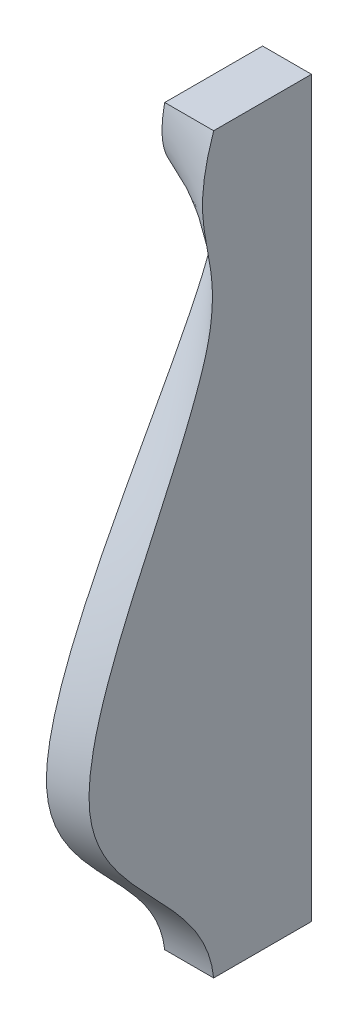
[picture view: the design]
ISO-10303-21;
HEADER;
FILE_DESCRIPTION(('STEP AP214'),'2;1');
FILE_NAME('part.step','',(''),(''),'','','');
FILE_SCHEMA(('AUTOMOTIVE_DESIGN { 1 0 10303 214 1 1 1 1 }'));
ENDSEC;
DATA;
#1=APPLICATION_CONTEXT('core data for automotive mechanical design processes');
#2=APPLICATION_PROTOCOL_DEFINITION('international standard','automotive_design',2000,#1);
#3=PRODUCT_CONTEXT('',#1,'mechanical');
#4=PRODUCT('Part','Part','',(#3));
#5=PRODUCT_RELATED_PRODUCT_CATEGORY('part','',(#4));
#6=PRODUCT_DEFINITION_FORMATION('','',#4);
#7=PRODUCT_DEFINITION_CONTEXT('part definition',#1,'design');
#8=PRODUCT_DEFINITION('design','',#6,#7);
#9=PRODUCT_DEFINITION_SHAPE('','',#8);
#10=(LENGTH_UNIT() NAMED_UNIT(*) SI_UNIT(.MILLI.,.METRE.));
#11=(NAMED_UNIT(*) PLANE_ANGLE_UNIT() SI_UNIT($,.RADIAN.));
#12=(NAMED_UNIT(*) SI_UNIT($,.STERADIAN.) SOLID_ANGLE_UNIT());
#13=UNCERTAINTY_MEASURE_WITH_UNIT(LENGTH_MEASURE(1.E-05),#10,'distance_accuracy_value','');
#14=(GEOMETRIC_REPRESENTATION_CONTEXT(3) GLOBAL_UNCERTAINTY_ASSIGNED_CONTEXT((#13)) GLOBAL_UNIT_ASSIGNED_CONTEXT((#10,
#11,#12)) REPRESENTATION_CONTEXT('',''));
#15=CARTESIAN_POINT('',(0.,0.,0.));
#16=DIRECTION('',(0.,0.,1.));
#17=DIRECTION('',(1.,0.,0.));
#18=AXIS2_PLACEMENT_3D('',#15,#16,#17);
#19=CARTESIAN_POINT('',(-50.0000000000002,375.,253.120113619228));
#20=DIRECTION('',(1.,0.,0.));
#21=DIRECTION('',(0.,0.,-1.));
#22=AXIS2_PLACEMENT_3D('',#19,#20,#21);
#23=PLANE('',#22);
#24=CARTESIAN_POINT('',(-50.0000000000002,375.,100.));
#25=CARTESIAN_POINT('',(-50.0000000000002,373.411982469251,100.545198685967));
#26=CARTESIAN_POINT('',(-50.0000000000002,371.819273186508,101.076878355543));
#27=CARTESIAN_POINT('',(-50.0000000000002,368.619545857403,102.112287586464));
#28=CARTESIAN_POINT('',(-50.0000000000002,367.012499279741,102.615928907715));
#29=CARTESIAN_POINT('',(-50.0000000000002,363.785265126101,103.592088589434));
#30=CARTESIAN_POINT('',(-50.0000000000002,362.165057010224,104.064539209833));
#31=CARTESIAN_POINT('',(-50.0000000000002,358.91265503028,104.974977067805));
#32=CARTESIAN_POINT('',(-50.0000000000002,357.280448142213,105.412917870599));
#33=CARTESIAN_POINT('',(-50.0000000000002,354.005173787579,106.250915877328));
#34=CARTESIAN_POINT('',(-50.0000000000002,352.362099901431,106.650948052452));
#35=CARTESIAN_POINT('',(-50.0000000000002,349.066198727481,107.409634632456));
#36=CARTESIAN_POINT('',(-50.0000000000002,347.413370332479,107.768284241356));
#37=CARTESIAN_POINT('',(-50.0000000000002,344.121758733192,108.436081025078));
#38=CARTESIAN_POINT('',(-50.0000000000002,342.483102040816,108.745849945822));
#39=CARTESIAN_POINT('',(-50.0000000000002,339.198566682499,109.318351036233));
#40=CARTESIAN_POINT('',(-50.0000000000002,337.552692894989,109.58111108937));
#41=CARTESIAN_POINT('',(-50.0000000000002,334.254898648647,110.056390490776));
#42=CARTESIAN_POINT('',(-50.0000000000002,332.602983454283,110.268946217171));
#43=CARTESIAN_POINT('',(-50.0000000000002,329.294313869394,110.640893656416));
#44=CARTESIAN_POINT('',(-50.0000000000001,327.637563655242,110.800322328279));
#45=CARTESIAN_POINT('',(-50.0000000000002,324.320503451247,111.063559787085));
#46=CARTESIAN_POINT('',(-50.0000000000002,322.660195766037,111.167397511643));
#47=CARTESIAN_POINT('',(-50.0000000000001,319.337335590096,111.317682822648));
#48=CARTESIAN_POINT('',(-50.0000000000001,317.674783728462,111.364144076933));
#49=CARTESIAN_POINT('',(-50.0000000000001,315.014921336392,111.391976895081));
#50=CARTESIAN_POINT('',(-50.0000000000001,314.017769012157,111.39196086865));
#51=CARTESIAN_POINT('',(-50.0000000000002,312.023543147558,111.371108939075));
#52=CARTESIAN_POINT('',(-50.0000000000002,311.026469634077,111.350270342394));
#53=CARTESIAN_POINT('',(-50.0000000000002,309.032886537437,111.288023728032));
#54=CARTESIAN_POINT('',(-50.0000000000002,308.036377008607,111.246613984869));
#55=CARTESIAN_POINT('',(-50.0000000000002,306.044380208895,111.143712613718));
#56=CARTESIAN_POINT('',(-50.0000000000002,305.04889295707,111.082220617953));
#57=CARTESIAN_POINT('',(-50.0000000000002,303.059393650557,110.939889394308));
#58=CARTESIAN_POINT('',(-50.0000000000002,302.065381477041,110.859051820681));
#59=CARTESIAN_POINT('',(-50.0000000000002,300.078665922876,110.678972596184));
#60=CARTESIAN_POINT('',(-50.0000000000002,299.085963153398,110.579724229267));
#61=CARTESIAN_POINT('',(-50.0000000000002,297.102491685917,110.364081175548));
#62=CARTESIAN_POINT('',(-50.0000000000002,296.111722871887,110.247687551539));
#63=CARTESIAN_POINT('',(-50.0000000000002,294.132144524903,109.999223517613));
#64=CARTESIAN_POINT('',(-50.0000000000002,293.143335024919,109.867152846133));
#65=CARTESIAN_POINT('',(-50.0000000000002,291.16766882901,109.589037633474));
#66=CARTESIAN_POINT('',(-50.0000000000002,290.180812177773,109.442992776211));
#67=CARTESIAN_POINT('',(-50.0000000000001,288.209016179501,109.138849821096));
#68=CARTESIAN_POINT('',(-50.0000000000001,287.224076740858,108.980752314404));
#69=CARTESIAN_POINT('',(-50.0000000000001,285.017115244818,108.615010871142));
#70=CARTESIAN_POINT('',(-50.0000000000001,283.795544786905,108.404651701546));
#71=CARTESIAN_POINT('',(-50.0000000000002,281.354453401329,107.972812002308));
#72=CARTESIAN_POINT('',(-50.0000000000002,280.134932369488,107.751332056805));
#73=CARTESIAN_POINT('',(-50.0000000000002,277.697092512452,107.301721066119));
#74=CARTESIAN_POINT('',(-50.0000000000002,276.478773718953,107.073589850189));
#75=CARTESIAN_POINT('',(-50.0000000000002,274.042478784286,106.615227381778));
#76=CARTESIAN_POINT('',(-50.0000000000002,272.824502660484,106.384996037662));
#77=CARTESIAN_POINT('',(-50.0000000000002,270.388187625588,105.926958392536));
#78=CARTESIAN_POINT('',(-50.0000000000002,269.169848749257,105.699151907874));
#79=CARTESIAN_POINT('',(-50.0000000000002,266.731957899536,105.250267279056));
#80=CARTESIAN_POINT('',(-50.0000000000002,265.512405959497,105.029188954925));
#81=CARTESIAN_POINT('',(-50.0000000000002,263.071441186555,104.597787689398));
#82=CARTESIAN_POINT('',(-50.0000000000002,261.850028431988,104.387464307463));
#83=CARTESIAN_POINT('',(-50.0000000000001,259.404766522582,103.981202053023));
#84=CARTESIAN_POINT('',(-50.0000000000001,258.180917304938,103.785263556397));
#85=CARTESIAN_POINT('',(-50.0000000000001,255.725906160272,103.410271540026));
#86=CARTESIAN_POINT('',(-50.0000000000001,254.494734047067,103.231284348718));
#87=CARTESIAN_POINT('',(-50.0000000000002,252.029566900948,102.893774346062));
#88=CARTESIAN_POINT('',(-50.0000000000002,250.795571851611,102.735251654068));
#89=CARTESIAN_POINT('',(-50.0000000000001,248.324845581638,102.440907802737));
#90=CARTESIAN_POINT('',(-50.0000000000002,247.088114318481,102.30508699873));
#91=CARTESIAN_POINT('',(-50.0000000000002,244.612204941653,102.057897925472));
#92=CARTESIAN_POINT('',(-50.0000000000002,243.373026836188,101.946529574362));
#93=CARTESIAN_POINT('',(-50.0000000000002,240.892541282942,101.74953172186));
#94=CARTESIAN_POINT('',(-50.0000000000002,239.651233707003,101.663903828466));
#95=CARTESIAN_POINT('',(-50.0000000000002,237.167053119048,101.519287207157));
#96=CARTESIAN_POINT('',(-50.0000000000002,235.924180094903,101.460298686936));
#97=CARTESIAN_POINT('',(-50.0000000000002,233.437450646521,101.369514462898));
#98=CARTESIAN_POINT('',(-50.0000000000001,232.193594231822,101.337718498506));
#99=CARTESIAN_POINT('',(-50.0000000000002,229.705512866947,101.301597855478));
#100=CARTESIAN_POINT('',(-50.0000000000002,228.461287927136,101.297272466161));
#101=CARTESIAN_POINT('',(-50.0000000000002,226.014355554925,101.315845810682));
#102=CARTESIAN_POINT('',(-50.0000000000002,224.811641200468,101.337845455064));
#103=CARTESIAN_POINT('',(-50.0000000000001,222.406947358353,101.407509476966));
#104=CARTESIAN_POINT('',(-50.0000000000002,221.204967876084,101.455174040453));
#105=CARTESIAN_POINT('',(-50.0000000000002,218.802219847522,101.57600354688));
#106=CARTESIAN_POINT('',(-50.0000000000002,217.601451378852,101.649170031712));
#107=CARTESIAN_POINT('',(-50.0000000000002,215.20159708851,101.820780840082));
#108=CARTESIAN_POINT('',(-50.0000000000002,214.002511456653,101.91922781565));
#109=CARTESIAN_POINT('',(-50.0000000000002,211.607293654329,102.1410660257));
#110=CARTESIAN_POINT('',(-50.0000000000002,210.411160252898,102.2644439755));
#111=CARTESIAN_POINT('',(-50.0000000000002,208.021735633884,102.53587570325));
#112=CARTESIAN_POINT('',(-50.0000000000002,206.828444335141,102.683928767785));
#113=CARTESIAN_POINT('',(-50.0000000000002,204.445356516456,103.004369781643));
#114=CARTESIAN_POINT('',(-50.0000000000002,203.255559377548,103.176753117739));
#115=CARTESIAN_POINT('',(-50.0000000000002,201.473899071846,103.453307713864));
#116=CARTESIAN_POINT('',(-50.0000000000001,200.880624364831,103.548470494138));
#117=CARTESIAN_POINT('',(-50.0000000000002,199.695052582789,103.744754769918));
#118=CARTESIAN_POINT('',(-50.0000000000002,199.102755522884,103.845876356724));
#119=CARTESIAN_POINT('',(-50.0000000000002,197.130475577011,104.192750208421));
#120=CARTESIAN_POINT('',(-50.0000000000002,195.75278139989,104.451640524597));
#121=CARTESIAN_POINT('',(-50.0000000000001,193.003675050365,105.001008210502));
#122=CARTESIAN_POINT('',(-50.0000000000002,191.632263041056,105.291486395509));
#123=CARTESIAN_POINT('',(-50.0000000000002,189.580210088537,105.750428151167));
#124=CARTESIAN_POINT('',(-50.0000000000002,188.896957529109,105.90729905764));
#125=CARTESIAN_POINT('',(-50.0000000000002,187.532247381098,106.228672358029));
#126=CARTESIAN_POINT('',(-50.0000000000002,186.85078978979,106.393174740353));
#127=CARTESIAN_POINT('',(-50.0000000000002,185.489760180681,106.729773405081));
#128=CARTESIAN_POINT('',(-50.0000000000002,184.810188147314,106.90186962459));
#129=CARTESIAN_POINT('',(-50.0000000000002,183.452899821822,107.253227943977));
#130=CARTESIAN_POINT('',(-50.0000000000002,182.775183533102,107.432490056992));
#131=CARTESIAN_POINT('',(-50.0000000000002,181.420723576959,107.797758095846));
#132=CARTESIAN_POINT('',(-50.0000000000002,180.74398196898,107.983771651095));
#133=CARTESIAN_POINT('',(-50.0000000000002,179.392190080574,108.361835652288));
#134=CARTESIAN_POINT('',(-50.0000000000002,178.717139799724,108.553886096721));
#135=CARTESIAN_POINT('',(-50.0000000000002,176.694391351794,109.138372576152));
#136=CARTESIAN_POINT('',(-50.0000000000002,175.349096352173,109.539143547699));
#137=CARTESIAN_POINT('',(-50.0000000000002,172.662564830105,110.360205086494));
#138=CARTESIAN_POINT('',(-50.0000000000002,171.32133597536,110.780520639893));
#139=CARTESIAN_POINT('',(-50.0000000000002,168.644137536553,111.637527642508));
#140=CARTESIAN_POINT('',(-50.0000000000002,167.308167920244,112.07421899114));
#141=CARTESIAN_POINT('',(-50.0000000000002,164.639977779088,112.962081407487));
#142=CARTESIAN_POINT('',(-50.0000000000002,163.307760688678,113.41326277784));
#143=CARTESIAN_POINT('',(-50.0000000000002,160.647555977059,114.327931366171));
#144=CARTESIAN_POINT('',(-50.0000000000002,159.31956837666,114.791418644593));
#145=CARTESIAN_POINT('',(-50.0000000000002,156.66765038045,115.728992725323));
#146=CARTESIAN_POINT('',(-50.0000000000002,155.343719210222,116.203077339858));
#147=CARTESIAN_POINT('',(-50.0000000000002,152.699244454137,117.16059124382));
#148=CARTESIAN_POINT('',(-50.0000000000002,151.378700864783,117.644020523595));
#149=CARTESIAN_POINT('',(-50.0000000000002,148.729259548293,118.623985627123));
#150=CARTESIAN_POINT('',(-50.0000000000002,147.40039064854,119.12059937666));
#151=CARTESIAN_POINT('',(-50.0000000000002,144.745842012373,120.122270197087));
#152=CARTESIAN_POINT('',(-50.0000000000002,143.420162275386,120.627327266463));
#153=CARTESIAN_POINT('',(-50.0000000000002,139.450536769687,122.153367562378));
#154=CARTESIAN_POINT('',(-50.0000000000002,136.811166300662,123.186272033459));
#155=CARTESIAN_POINT('',(-50.0000000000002,131.545797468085,125.279632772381));
#156=CARTESIAN_POINT('',(-50.0000000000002,128.919790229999,126.340066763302));
#157=CARTESIAN_POINT('',(-50.0000000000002,123.67954195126,128.485549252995));
#158=CARTESIAN_POINT('',(-50.0000000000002,121.065295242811,129.570583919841));
#159=CARTESIAN_POINT('',(-50.0000000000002,115.847026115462,131.76244788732));
#160=CARTESIAN_POINT('',(-50.0000000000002,113.243000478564,132.869269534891));
#161=CARTESIAN_POINT('',(-50.0000000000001,108.043661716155,135.101966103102));
#162=CARTESIAN_POINT('',(-50.0000000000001,105.448347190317,136.227837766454));
#163=CARTESIAN_POINT('',(-50.0000000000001,97.4585446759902,139.723914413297));
#164=CARTESIAN_POINT('',(-50.0000000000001,92.0760164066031,142.121443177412));
#165=CARTESIAN_POINT('',(-50.0000000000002,81.3307462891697,146.963298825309));
#166=CARTESIAN_POINT('',(-50.0000000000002,75.96800903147,149.40763584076));
#167=CARTESIAN_POINT('',(-50.0000000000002,65.2512156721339,154.320720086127));
#168=CARTESIAN_POINT('',(-50.0000000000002,59.8971637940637,156.789476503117));
#169=CARTESIAN_POINT('',(-50.0000000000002,49.1874266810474,161.730610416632));
#170=CARTESIAN_POINT('',(-50.0000000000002,43.8317420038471,164.202989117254));
#171=CARTESIAN_POINT('',(-50.0000000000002,33.1089723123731,169.131773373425));
#172=CARTESIAN_POINT('',(-50.0000000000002,27.7418822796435,171.588168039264));
#173=CARTESIAN_POINT('',(-50.0000000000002,16.9867450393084,176.465915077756));
#174=CARTESIAN_POINT('',(-50.0000000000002,11.598684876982,178.887239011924));
#175=CARTESIAN_POINT('',(-50.0000000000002,3.51580203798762,182.468460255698));
#176=CARTESIAN_POINT('',(-50.0000000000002,0.830489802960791,183.649815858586));
#177=CARTESIAN_POINT('',(-50.0000000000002,-4.54738764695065,185.995890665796));
#178=CARTESIAN_POINT('',(-50.0000000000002,-7.23995283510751,187.160609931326));
#179=CARTESIAN_POINT('',(-50.0000000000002,-12.6336507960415,189.470838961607));
#180=CARTESIAN_POINT('',(-50.0000000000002,-15.3347844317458,190.616346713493));
#181=CARTESIAN_POINT('',(-50.0000000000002,-20.7463716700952,192.885153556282));
#182=CARTESIAN_POINT('',(-50.0000000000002,-23.4568252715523,194.008452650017));
#183=CARTESIAN_POINT('',(-50.0000000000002,-28.8866154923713,196.229144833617));
#184=CARTESIAN_POINT('',(-50.0000000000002,-31.6059464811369,197.326551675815));
#185=CARTESIAN_POINT('',(-50.0000000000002,-37.0560076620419,199.49272890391));
#186=CARTESIAN_POINT('',(-50.0000000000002,-39.786737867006,200.56149925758));
#187=CARTESIAN_POINT('',(-50.0000000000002,-45.2580758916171,202.66571006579));
#188=CARTESIAN_POINT('',(-50.0000000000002,-47.9986719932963,203.70118094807));
#189=CARTESIAN_POINT('',(-50.0000000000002,-53.4933482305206,205.73573753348));
#190=CARTESIAN_POINT('',(-50.0000000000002,-56.2474283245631,206.73482334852));
#191=CARTESIAN_POINT('',(-50.0000000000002,-61.7675105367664,208.691072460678));
#192=CARTESIAN_POINT('',(-50.0000000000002,-64.5334988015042,209.648274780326));
#193=CARTESIAN_POINT('',(-50.0000000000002,-70.0810788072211,211.516571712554));
#194=CARTESIAN_POINT('',(-50.0000000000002,-72.8626707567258,212.42766570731));
#195=CARTESIAN_POINT('',(-50.0000000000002,-78.4416543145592,214.197529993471));
#196=CARTESIAN_POINT('',(-50.0000000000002,-81.2390414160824,215.056314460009));
#197=CARTESIAN_POINT('',(-50.0000000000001,-86.8511709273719,216.714934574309));
#198=CARTESIAN_POINT('',(-50.0000000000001,-89.6659125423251,217.51477290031));
#199=CARTESIAN_POINT('',(-50.0000000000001,-94.6743474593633,218.874027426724));
#200=CARTESIAN_POINT('',(-50.0000000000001,-96.8643935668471,219.446882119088));
#201=CARTESIAN_POINT('',(-50.0000000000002,-101.25595796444,220.548333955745));
#202=CARTESIAN_POINT('',(-50.0000000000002,-103.457477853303,221.076924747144));
#203=CARTESIAN_POINT('',(-50.0000000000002,-107.871991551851,222.084960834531));
#204=CARTESIAN_POINT('',(-50.0000000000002,-110.084986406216,222.56440157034));
#205=CARTESIAN_POINT('',(-50.0000000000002,-114.522606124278,223.468640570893));
#206=CARTESIAN_POINT('',(-50.0000000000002,-116.74723315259,223.893428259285));
#207=CARTESIAN_POINT('',(-50.0000000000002,-121.204627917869,224.681442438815));
#208=CARTESIAN_POINT('',(-50.0000000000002,-123.437382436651,225.044743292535));
#209=CARTESIAN_POINT('',(-50.0000000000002,-127.913023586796,225.703184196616));
#210=CARTESIAN_POINT('',(-50.0000000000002,-130.155910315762,225.998323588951));
#211=CARTESIAN_POINT('',(-50.0000000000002,-134.650160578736,226.512094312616));
#212=CARTESIAN_POINT('',(-50.0000000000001,-136.901522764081,226.730737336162));
#213=CARTESIAN_POINT('',(-50.0000000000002,-141.41131933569,227.082095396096));
#214=CARTESIAN_POINT('',(-50.0000000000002,-143.669754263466,227.21480368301));
#215=CARTESIAN_POINT('',(-50.0000000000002,-147.313616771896,227.350686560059));
#216=CARTESIAN_POINT('',(-50.0000000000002,-148.697949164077,227.384136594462));
#217=CARTESIAN_POINT('',(-50.0000000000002,-151.467085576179,227.411976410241));
#218=CARTESIAN_POINT('',(-50.0000000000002,-152.851889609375,227.406364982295));
#219=CARTESIAN_POINT('',(-50.0000000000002,-155.620457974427,227.353140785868));
#220=CARTESIAN_POINT('',(-50.0000000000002,-157.004222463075,227.305536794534));
#221=CARTESIAN_POINT('',(-50.0000000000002,-159.077945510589,227.200299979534));
#222=CARTESIAN_POINT('',(-50.0000000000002,-159.768792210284,227.159588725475));
#223=CARTESIAN_POINT('',(-50.0000000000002,-161.149705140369,227.066480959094));
#224=CARTESIAN_POINT('',(-50.0000000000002,-161.839771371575,227.014084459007));
#225=CARTESIAN_POINT('',(-50.0000000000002,-163.21884301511,226.897196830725));
#226=CARTESIAN_POINT('',(-50.0000000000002,-163.907848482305,226.832706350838));
#227=CARTESIAN_POINT('',(-50.0000000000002,-165.284572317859,226.69119482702));
#228=CARTESIAN_POINT('',(-50.0000000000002,-165.972290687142,226.614173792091));
#229=CARTESIAN_POINT('',(-50.0000000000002,-167.344498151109,226.447780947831));
#230=CARTESIAN_POINT('',(-50.0000000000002,-168.028991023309,226.358440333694));
#231=CARTESIAN_POINT('',(-50.0000000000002,-169.396224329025,226.167279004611));
#232=CARTESIAN_POINT('',(-50.0000000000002,-170.078964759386,226.065458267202));
#233=CARTESIAN_POINT('',(-50.0000000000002,-172.124612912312,225.741255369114));
#234=CARTESIAN_POINT('',(-50.0000000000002,-173.484607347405,225.500173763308));
#235=CARTESIAN_POINT('',(-50.0000000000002,-176.195149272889,224.968679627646));
#236=CARTESIAN_POINT('',(-50.0000000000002,-177.545694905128,224.678257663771));
#237=CARTESIAN_POINT('',(-50.0000000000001,-180.235587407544,224.049109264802));
#238=CARTESIAN_POINT('',(-50.0000000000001,-181.57493353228,223.710379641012));
#239=CARTESIAN_POINT('',(-50.0000000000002,-184.240605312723,222.985687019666));
#240=CARTESIAN_POINT('',(-50.0000000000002,-185.566932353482,222.59972910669));
#241=CARTESIAN_POINT('',(-50.0000000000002,-188.53155439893,221.680531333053));
#242=CARTESIAN_POINT('',(-50.0000000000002,-190.165888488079,221.134472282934));
#243=CARTESIAN_POINT('',(-50.0000000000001,-193.410064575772,219.973460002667));
#244=CARTESIAN_POINT('',(-50.0000000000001,-195.019903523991,219.358498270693));
#245=CARTESIAN_POINT('',(-50.0000000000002,-198.212818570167,218.063297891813));
#246=CARTESIAN_POINT('',(-50.0000000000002,-199.795898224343,217.383068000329));
#247=CARTESIAN_POINT('',(-50.0000000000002,-202.934127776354,215.961203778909));
#248=CARTESIAN_POINT('',(-50.0000000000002,-204.489278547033,215.219571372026));
#249=CARTESIAN_POINT('',(-50.0000000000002,-207.574998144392,213.677064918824));
#250=CARTESIAN_POINT('',(-50.0000000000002,-209.105491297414,212.876039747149));
#251=CARTESIAN_POINT('',(-50.0000000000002,-212.137461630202,211.220886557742));
#252=CARTESIAN_POINT('',(-50.0000000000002,-213.638938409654,210.366757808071));
#253=CARTESIAN_POINT('',(-50.0000000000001,-216.613104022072,208.609890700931));
#254=CARTESIAN_POINT('',(-50.0000000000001,-218.085793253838,207.707153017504));
#255=CARTESIAN_POINT('',(-50.0000000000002,-221.003169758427,205.85746014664));
#256=CARTESIAN_POINT('',(-50.0000000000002,-222.447855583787,204.910502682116));
#257=CARTESIAN_POINT('',(-50.0000000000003,-226.047939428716,202.478358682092));
#258=CARTESIAN_POINT('',(-50.0000000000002,-228.185888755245,200.967308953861));
#259=CARTESIAN_POINT('',(-50.0000000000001,-232.405149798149,197.867873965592));
#260=CARTESIAN_POINT('',(-50.0000000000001,-234.486453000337,196.279477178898));
#261=CARTESIAN_POINT('',(-50.0000000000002,-238.599227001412,193.038251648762));
#262=CARTESIAN_POINT('',(-50.0000000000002,-240.630681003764,191.385401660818));
#263=CARTESIAN_POINT('',(-50.0000000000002,-244.650240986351,188.02795883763));
#264=CARTESIAN_POINT('',(-50.0000000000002,-246.638346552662,186.323365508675));
#265=CARTESIAN_POINT('',(-50.0000000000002,-250.582685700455,182.870344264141));
#266=CARTESIAN_POINT('',(-50.0000000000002,-252.538851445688,181.121839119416));
#267=CARTESIAN_POINT('',(-50.0000000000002,-256.422984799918,177.595013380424));
#268=CARTESIAN_POINT('',(-50.0000000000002,-258.350960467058,175.816701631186));
#269=CARTESIAN_POINT('',(-50.0000000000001,-262.187478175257,172.239609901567));
#270=CARTESIAN_POINT('',(-50.0000000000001,-264.096021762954,170.440831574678));
#271=CARTESIAN_POINT('',(-50.0000000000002,-267.902261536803,166.831967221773));
#272=CARTESIAN_POINT('',(-50.0000000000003,-269.799957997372,165.021881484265));
#273=CARTESIAN_POINT('',(-50.0000000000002,-273.243548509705,161.733269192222));
#274=CARTESIAN_POINT('',(-50.0000000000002,-274.789811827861,160.255128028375));
#275=CARTESIAN_POINT('',(-50.0000000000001,-277.885564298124,157.302255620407));
#276=CARTESIAN_POINT('',(-50.0000000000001,-279.435053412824,155.82752433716));
#277=CARTESIAN_POINT('',(-50.0000000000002,-282.542093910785,152.886426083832));
#278=CARTESIAN_POINT('',(-50.0000000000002,-284.099645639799,151.420059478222));
#279=CARTESIAN_POINT('',(-50.0000000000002,-287.227770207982,148.500773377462));
#280=CARTESIAN_POINT('',(-50.0000000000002,-288.798344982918,147.047855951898));
#281=CARTESIAN_POINT('',(-50.0000000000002,-291.957647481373,144.160733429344));
#282=CARTESIAN_POINT('',(-50.0000000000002,-293.546381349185,142.726535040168));
#283=CARTESIAN_POINT('',(-50.0000000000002,-296.742703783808,139.886496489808));
#284=CARTESIAN_POINT('',(-50.0000000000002,-298.35024229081,138.480600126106));
#285=CARTESIAN_POINT('',(-50.0000000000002,-301.59250613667,135.700183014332));
#286=CARTESIAN_POINT('',(-50.0000000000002,-303.227233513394,134.325664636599));
#287=CARTESIAN_POINT('',(-50.0000000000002,-306.527918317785,131.615491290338));
#288=CARTESIAN_POINT('',(-50.0000000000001,-308.193866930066,130.279825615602));
#289=CARTESIAN_POINT('',(-50.0000000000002,-311.561222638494,127.655095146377));
#290=CARTESIAN_POINT('',(-50.0000000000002,-313.262616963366,126.366014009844));
#291=CARTESIAN_POINT('',(-50.0000000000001,-316.70533439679,123.842420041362));
#292=CARTESIAN_POINT('',(-50.0000000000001,-318.446654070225,122.6079025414));
#293=CARTESIAN_POINT('',(-50.0000000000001,-321.605045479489,120.453299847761));
#294=CARTESIAN_POINT('',(-50.0000000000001,-323.014007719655,119.521330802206));
#295=CARTESIAN_POINT('',(-50.0000000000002,-325.860656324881,117.701936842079));
#296=CARTESIAN_POINT('',(-50.0000000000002,-327.298345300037,116.814516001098));
#297=CARTESIAN_POINT('',(-50.0000000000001,-330.203280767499,115.089321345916));
#298=CARTESIAN_POINT('',(-50.0000000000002,-331.670527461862,114.251547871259));
#299=CARTESIAN_POINT('',(-50.0000000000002,-334.635353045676,112.630622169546));
#300=CARTESIAN_POINT('',(-50.0000000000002,-336.132938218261,111.847481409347));
#301=CARTESIAN_POINT('',(-50.0000000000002,-339.153065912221,110.343647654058));
#302=CARTESIAN_POINT('',(-50.0000000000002,-340.6755103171,109.622758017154));
#303=CARTESIAN_POINT('',(-50.0000000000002,-343.749495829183,108.245490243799));
#304=CARTESIAN_POINT('',(-50.0000000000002,-345.301038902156,107.589116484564));
#305=CARTESIAN_POINT('',(-50.0000000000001,-348.431147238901,106.345826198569));
#306=CARTESIAN_POINT('',(-50.0000000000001,-350.009703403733,105.758886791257));
#307=CARTESIAN_POINT('',(-50.0000000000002,-353.191582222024,104.658630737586));
#308=CARTESIAN_POINT('',(-50.0000000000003,-354.79489311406,104.145280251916));
#309=CARTESIAN_POINT('',(-50.0000000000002,-357.166677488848,103.447598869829));
#310=CARTESIAN_POINT('',(-50.0000000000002,-357.926439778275,103.233288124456));
#311=CARTESIAN_POINT('',(-50.0000000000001,-359.45052112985,102.821870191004));
#312=CARTESIAN_POINT('',(-50.0000000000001,-360.214839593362,102.624760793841));
#313=CARTESIAN_POINT('',(-50.0000000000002,-361.747685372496,102.247995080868));
#314=CARTESIAN_POINT('',(-50.0000000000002,-362.516212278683,102.068337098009));
#315=CARTESIAN_POINT('',(-50.0000000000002,-364.057138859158,101.726665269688));
#316=CARTESIAN_POINT('',(-50.0000000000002,-364.829538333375,101.564650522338));
#317=CARTESIAN_POINT('',(-50.0000000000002,-366.380628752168,101.257864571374));
#318=CARTESIAN_POINT('',(-50.0000000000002,-367.159332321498,101.113157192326));
#319=CARTESIAN_POINT('',(-50.0000000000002,-368.71991517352,100.841762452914));
#320=CARTESIAN_POINT('',(-50.0000000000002,-369.501794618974,100.71507602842));
#321=CARTESIAN_POINT('',(-50.0000000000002,-371.068358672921,100.479778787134));
#322=CARTESIAN_POINT('',(-50.0000000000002,-371.853043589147,100.371170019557));
#323=CARTESIAN_POINT('',(-50.0000000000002,-373.42484081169,100.172023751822));
#324=CARTESIAN_POINT('',(-50.0000000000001,-374.211953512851,100.081489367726));
#325=CARTESIAN_POINT('',(-50.0000000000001,-375.,100.));
#326=B_SPLINE_CURVE_WITH_KNOTS('',3,(#24,#25,#26,#27,#28,#29,#30,#31,#32,#33,#34,#35,#36,#37,
#38,#39,#40,#41,#42,#43,#44,#45,#46,#47,#48,#49,#50,#51,#52,#53,#54,#55,#56,#57,#58,#59,#60,#61,
#62,#63,#64,#65,#66,#67,#68,#69,#70,#71,#72,#73,#74,#75,#76,#77,#78,#79,#80,#81,#82,#83,#84,#85,
#86,#87,#88,#89,#90,#91,#92,#93,#94,#95,#96,#97,#98,#99,#100,#101,#102,#103,#104,#105,#106,#107,
#108,#109,#110,#111,#112,#113,#114,#115,#116,#117,#118,#119,#120,#121,#122,#123,#124,#125,#126,
#127,#128,#129,#130,#131,#132,#133,#134,#135,#136,#137,#138,#139,#140,#141,#142,#143,#144,#145,
#146,#147,#148,#149,#150,#151,#152,#153,#154,#155,#156,#157,#158,#159,#160,#161,#162,#163,#164,
#165,#166,#167,#168,#169,#170,#171,#172,#173,#174,#175,#176,#177,#178,#179,#180,#181,#182,#183,
#184,#185,#186,#187,#188,#189,#190,#191,#192,#193,#194,#195,#196,#197,#198,#199,#200,#201,#202,
#203,#204,#205,#206,#207,#208,#209,#210,#211,#212,#213,#214,#215,#216,#217,#218,#219,#220,#221,
#222,#223,#224,#225,#226,#227,#228,#229,#230,#231,#232,#233,#234,#235,#236,#237,#238,#239,#240,
#241,#242,#243,#244,#245,#246,#247,#248,#249,#250,#251,#252,#253,#254,#255,#256,#257,#258,#259,
#260,#261,#262,#263,#264,#265,#266,#267,#268,#269,#270,#271,#272,#273,#274,#275,#276,#277,#278,
#279,#280,#281,#282,#283,#284,#285,#286,#287,#288,#289,#290,#291,#292,#293,#294,#295,#296,#297,
#298,#299,#300,#301,#302,#303,#304,#305,#306,#307,#308,#309,#310,#311,#312,#313,#314,#315,#316,
#317,#318,#319,#320,#321,#322,#323,#324,#325),.UNSPECIFIED.,.F.,.F.,(4,2,2,2,2,2,2,2,2,2,2,2,2,
2,2,2,2,2,2,2,2,2,2,2,2,2,2,2,2,2,2,2,2,2,2,2,2,2,2,2,2,2,2,2,2,2,2,2,2,2,2,2,2,2,2,2,2,2,2,2,2,
2,2,2,2,2,2,2,2,2,2,2,2,2,2,2,2,2,2,2,2,2,2,2,2,2,2,2,2,2,2,2,2,2,2,2,2,2,2,2,2,2,2,2,2,2,2,2,2,
2,2,2,2,2,2,2,2,2,2,2,2,2,2,2,2,2,2,2,2,2,2,2,2,2,2,2,2,2,2,2,2,2,2,2,2,2,2,2,2,2,4),(0.,
5.03701006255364,10.0890671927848,15.1517580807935,20.2211487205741,25.2938633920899,
30.3671653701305,35.3695687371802,40.3689950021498,45.3647874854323,50.3570972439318,
55.3468057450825,60.3353254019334,63.3265896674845,66.3182409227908,69.3101431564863,
72.3021001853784,75.2938014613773,78.2865962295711,81.2792055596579,84.2718648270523,
87.26459180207,90.25717208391,93.9757457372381,97.6941242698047,101.412598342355,
105.131235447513,108.849588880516,112.567842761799,116.285944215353,120.004142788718,
123.736336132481,127.468551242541,131.2008247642,134.933085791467,138.665579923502,
142.398103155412,146.130590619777,149.862981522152,153.471454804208,157.079954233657,
160.688671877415,164.297768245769,167.904946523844,171.512020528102,175.118411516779,
176.920960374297,178.723536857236,182.928555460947,187.13368262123,189.236734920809,
191.339784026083,193.442815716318,195.545851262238,197.651342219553,199.75683265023,
203.967815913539,208.184339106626,212.400836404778,216.620401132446,220.839986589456,
225.058708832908,229.277426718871,233.53329223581,237.789156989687,246.291805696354,
254.787776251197,263.279082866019,271.767458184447,280.254396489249,297.931030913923,
315.611535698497,333.298966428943,350.995409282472,368.702857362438,386.423939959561,
395.224946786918,404.025921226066,412.82781208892,421.629701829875,430.426806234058,
439.223920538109,448.012753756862,456.801559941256,465.581995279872,474.362548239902,
483.140711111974,491.918474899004,498.709256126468,505.501010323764,512.293394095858,
519.087090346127,525.872510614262,532.657996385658,539.442444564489,546.227425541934,
550.381159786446,554.535022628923,558.688017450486,560.764071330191,562.840123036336,
564.916063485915,566.99200244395,569.062778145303,571.133557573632,575.276143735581,
579.419522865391,583.563175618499,587.706382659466,592.874156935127,598.042569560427,
603.210289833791,608.377848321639,613.559039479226,618.740302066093,623.921492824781,
629.102950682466,636.954848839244,644.807920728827,652.663603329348,660.519360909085,
668.390064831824,676.258473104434,684.126250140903,691.993827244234,698.411187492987,
704.828473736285,711.246037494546,717.664572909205,724.085348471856,730.491777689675,
736.898689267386,743.303818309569,749.706678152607,756.108989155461,761.176161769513,
766.243796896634,771.31146667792,776.380196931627,781.432280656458,786.484706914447,
791.535463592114,796.583890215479,798.951958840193,801.319722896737,803.687260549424,
806.054677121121,808.430571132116,810.806588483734,813.182874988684,815.559570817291),.UNSPECIFIED.);
#327=CARTESIAN_POINT('',(-50.0000000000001,375.,100.));
#328=VERTEX_POINT('',#327);
#329=CARTESIAN_POINT('',(-50.0000000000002,-375.,100.));
#330=VERTEX_POINT('',#329);
#331=EDGE_CURVE('E88',#328,#330,#326,.T.);
#332=ORIENTED_EDGE('',*,*,#331,.T.);
#333=DIRECTION('',(0.,0.,-1.));
#334=VECTOR('',#333,1.);
#335=CARTESIAN_POINT('',(-50.0000000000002,-375.,253.120113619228));
#336=LINE('',#335,#334);
#337=CARTESIAN_POINT('',(-50.0000000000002,-375.,0.));
#338=VERTEX_POINT('',#337);
#339=EDGE_CURVE('E50',#330,#338,#336,.T.);
#340=ORIENTED_EDGE('',*,*,#339,.T.);
#341=DIRECTION('',(0.,-1.,0.));
#342=VECTOR('',#341,1.);
#343=CARTESIAN_POINT('',(-50.0000000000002,375.,0.));
#344=LINE('',#343,#342);
#345=CARTESIAN_POINT('',(-50.0000000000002,375.,0.));
#346=VERTEX_POINT('',#345);
#347=EDGE_CURVE('E87',#346,#338,#344,.T.);
#348=ORIENTED_EDGE('',*,*,#347,.F.);
#349=DIRECTION('',(0.,0.,-1.));
#350=VECTOR('',#349,1.);
#351=CARTESIAN_POINT('',(-50.0000000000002,375.,253.120113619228));
#352=LINE('',#351,#350);
#353=EDGE_CURVE('E65',#328,#346,#352,.T.);
#354=ORIENTED_EDGE('',*,*,#353,.F.);
#355=EDGE_LOOP('',(#332,#340,#348,#354));
#356=FACE_BOUND('',#355,.T.);
#357=ADVANCED_FACE('F35',(#356),#23,.T.);
#358=CARTESIAN_POINT('',(0.,0.,0.));
#359=DIRECTION('',(0.,0.,-1.));
#360=DIRECTION('',(-1.,0.,0.));
#361=AXIS2_PLACEMENT_3D('',#358,#359,#360);
#362=PLANE('',#361);
#363=DIRECTION('',(1.,0.,0.));
#364=VECTOR('',#363,1.);
#365=CARTESIAN_POINT('',(-750.,-375.,0.));
#366=LINE('',#365,#364);
#367=CARTESIAN_POINT('',(-100.,-375.,0.));
#368=VERTEX_POINT('',#367);
#369=EDGE_CURVE('E79',#368,#338,#366,.T.);
#370=ORIENTED_EDGE('',*,*,#369,.F.);
#371=DIRECTION('',(0.,1.,0.));
#372=VECTOR('',#371,1.);
#373=CARTESIAN_POINT('',(-100.,375.,0.));
#374=LINE('',#373,#372);
#375=CARTESIAN_POINT('',(-100.,375.,0.));
#376=VERTEX_POINT('',#375);
#377=EDGE_CURVE('E157',#368,#376,#374,.T.);
#378=ORIENTED_EDGE('',*,*,#377,.T.);
#379=DIRECTION('',(-1.,0.,0.));
#380=VECTOR('',#379,1.);
#381=CARTESIAN_POINT('',(-750.,375.,0.));
#382=LINE('',#381,#380);
#383=EDGE_CURVE('E93',#346,#376,#382,.T.);
#384=ORIENTED_EDGE('',*,*,#383,.F.);
#385=ORIENTED_EDGE('',*,*,#347,.T.);
#386=EDGE_LOOP('',(#370,#378,#384,#385));
#387=FACE_BOUND('',#386,.T.);
#388=ADVANCED_FACE('F91',(#387),#362,.T.);
#389=CARTESIAN_POINT('',(750.,-375.,100.));
#390=CARTESIAN_POINT('',(750.,-302.078506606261,100.));
#391=CARTESIAN_POINT('',(750.,-224.483786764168,100.));
#392=CARTESIAN_POINT('',(750.,-61.5160152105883,100.));
#393=CARTESIAN_POINT('',(750.,39.4445673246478,100.));
#394=CARTESIAN_POINT('',(750.,211.849847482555,100.));
#395=CARTESIAN_POINT('',(750.,298.882075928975,100.));
#396=CARTESIAN_POINT('',(750.,375.,100.));
#397=CARTESIAN_POINT('',(669.085175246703,-375.,100.));
#398=CARTESIAN_POINT('',(669.085175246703,-302.078506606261,100.));
#399=CARTESIAN_POINT('',(669.085175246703,-234.282472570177,121.198481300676));
#400=CARTESIAN_POINT('',(669.085175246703,-62.2283080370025,120.288550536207));
#401=CARTESIAN_POINT('',(669.085175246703,68.0647781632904,82.7868169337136));
#402=CARTESIAN_POINT('',(669.085175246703,240.312514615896,73.0426687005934));
#403=CARTESIAN_POINT('',(669.085175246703,298.882075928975,100.));
#404=CARTESIAN_POINT('',(669.085175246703,375.,100.));
#405=CARTESIAN_POINT('',(500.445116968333,-375.,100.));
#406=CARTESIAN_POINT('',(517.991528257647,-284.627602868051,95.5040591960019));
#407=CARTESIAN_POINT('',(530.038001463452,-221.673003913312,150.719602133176));
#408=CARTESIAN_POINT('',(473.74510655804,-71.7416270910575,167.060530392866));
#409=CARTESIAN_POINT('',(387.213321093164,45.6135081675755,91.591323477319));
#410=CARTESIAN_POINT('',(378.694107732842,207.638743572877,66.6461848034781));
#411=CARTESIAN_POINT('',(433.17831170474,253.396603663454,122.492891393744));
#412=CARTESIAN_POINT('',(500.445116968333,375.,100.));
#413=CARTESIAN_POINT('',(285.091607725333,-375.,100.));
#414=CARTESIAN_POINT('',(309.270321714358,-264.297524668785,86.4064578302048));
#415=CARTESIAN_POINT('',(325.856840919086,-200.08226970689,164.07204721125));
#416=CARTESIAN_POINT('',(247.47112957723,-80.9425320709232,234.992870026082));
#417=CARTESIAN_POINT('',(127.240382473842,2.40271344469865,186.756001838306));
#418=CARTESIAN_POINT('',(115.567806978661,152.518027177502,151.057444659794));
#419=CARTESIAN_POINT('',(191.428893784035,202.025100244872,189.039851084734));
#420=CARTESIAN_POINT('',(285.091607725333,375.,100.));
#421=CARTESIAN_POINT('',(47.4554331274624,-375.,100.));
#422=CARTESIAN_POINT('',(51.0669239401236,-278.639867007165,99.5141662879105));
#423=CARTESIAN_POINT('',(52.9210710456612,-231.452124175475,201.325948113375));
#424=CARTESIAN_POINT('',(3.18149891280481,-90.8615864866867,272.445475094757));
#425=CARTESIAN_POINT('',(-61.0346058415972,45.7948958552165,186.157760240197));
#426=CARTESIAN_POINT('',(-59.6612105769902,205.286893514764,133.941969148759));
#427=CARTESIAN_POINT('',(-11.8049718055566,220.40073671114,189.8209162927));
#428=CARTESIAN_POINT('',(47.4554331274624,375.,100.));
#429=CARTESIAN_POINT('',(-175.903454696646,-375.,100.));
#430=CARTESIAN_POINT('',(-199.823715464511,-320.588060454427,126.731848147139));
#431=CARTESIAN_POINT('',(-216.967937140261,-300.821135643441,242.921959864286));
#432=CARTESIAN_POINT('',(-184.265304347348,-55.1410097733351,206.147478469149));
#433=CARTESIAN_POINT('',(-119.865061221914,249.096629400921,-32.5779079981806));
#434=CARTESIAN_POINT('',(-104.641938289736,431.262460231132,-94.4845569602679));
#435=CARTESIAN_POINT('',(-136.623034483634,348.137040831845,60.785640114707));
#436=CARTESIAN_POINT('',(-175.903454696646,375.,100.));
#437=CARTESIAN_POINT('',(-355.235514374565,-375.,100.));
#438=CARTESIAN_POINT('',(-319.200833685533,-282.590755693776,58.2859511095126));
#439=CARTESIAN_POINT('',(-293.075279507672,-226.888141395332,104.97090627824));
#440=CARTESIAN_POINT('',(-324.119079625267,-68.6572837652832,122.102733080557));
#441=CARTESIAN_POINT('',(-398.972481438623,73.039345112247,53.3701087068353));
#442=CARTESIAN_POINT('',(-423.398679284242,233.384819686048,47.4380317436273));
#443=CARTESIAN_POINT('',(-392.720188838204,253.575952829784,124.952096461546));
#444=CARTESIAN_POINT('',(-355.235514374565,375.,100.));
#445=CARTESIAN_POINT('',(-536.684515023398,-375.,100.));
#446=CARTESIAN_POINT('',(-494.827225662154,-277.129657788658,52.0422385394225));
#447=CARTESIAN_POINT('',(-464.573647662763,-205.017596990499,67.039018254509));
#448=CARTESIAN_POINT('',(-506.334367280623,-72.2467511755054,96.5036749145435));
#449=CARTESIAN_POINT('',(-600.216684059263,9.35641022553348,95.9941925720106));
#450=CARTESIAN_POINT('',(-628.122542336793,166.946160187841,106.349064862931));
#451=CARTESIAN_POINT('',(-587.011939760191,237.095914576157,138.331902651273));
#452=CARTESIAN_POINT('',(-536.684515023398,375.,100.));
#453=CARTESIAN_POINT('',(-644.685568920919,-375.,100.));
#454=CARTESIAN_POINT('',(-644.685568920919,-302.078506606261,100.));
#455=CARTESIAN_POINT('',(-644.685568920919,-237.237234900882,127.59081546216));
#456=CARTESIAN_POINT('',(-644.685568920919,-62.4430976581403,126.406497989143));
#457=CARTESIAN_POINT('',(-644.685568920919,76.6951111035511,77.5962366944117));
#458=CARTESIAN_POINT('',(-644.685568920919,248.895340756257,64.9137717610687));
#459=CARTESIAN_POINT('',(-644.685568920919,298.882075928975,100.));
#460=CARTESIAN_POINT('',(-644.685568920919,375.,100.));
#461=CARTESIAN_POINT('',(-750.,-375.,100.));
#462=CARTESIAN_POINT('',(-750.,-302.078506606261,100.));
#463=CARTESIAN_POINT('',(-750.,-224.483786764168,100.));
#464=CARTESIAN_POINT('',(-750.,-61.5160152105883,100.));
#465=CARTESIAN_POINT('',(-750.,39.4445673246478,100.));
#466=CARTESIAN_POINT('',(-750.,211.849847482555,100.));
#467=CARTESIAN_POINT('',(-750.,298.882075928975,100.));
#468=CARTESIAN_POINT('',(-750.,375.,100.));
#469=B_SPLINE_SURFACE_WITH_KNOTS('',3,3,((#389,#390,#391,#392,#393,#394,#395,#396),(#397,#398,
#399,#400,#401,#402,#403,#404),(#405,#406,#407,#408,#409,#410,#411,#412),(#413,#414,#415,#416,
#417,#418,#419,#420),(#421,#422,#423,#424,#425,#426,#427,#428),(#429,#430,#431,#432,#433,#434,
#435,#436),(#437,#438,#439,#440,#441,#442,#443,#444),(#445,#446,#447,#448,#449,#450,#451,#452),
(#453,#454,#455,#456,#457,#458,#459,#460),(#461,#462,#463,#464,#465,#466,#467,#468)),
.UNSPECIFIED.,.F.,.F.,.F.,(4,1,1,1,1,1,1,4),(4,1,1,1,1,4),(0.,0.161829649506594,
0.33728011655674,0.430707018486,0.637101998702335,0.783997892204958,0.789371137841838,1.),(0.,
0.291685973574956,0.310378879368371,0.65187108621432,0.695528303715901,1.),.UNSPECIFIED.);
#470=CARTESIAN_POINT('',(-100.,-375.,100.));
#471=CARTESIAN_POINT('',(-100.,-374.116781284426,100.105613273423));
#472=CARTESIAN_POINT('',(-100.,-373.235085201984,100.223962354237));
#473=CARTESIAN_POINT('',(-100.,-371.475479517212,100.486029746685));
#474=CARTESIAN_POINT('',(-100.,-370.597569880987,100.629747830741));
#475=CARTESIAN_POINT('',(-100.,-368.847333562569,100.942261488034));
#476=CARTESIAN_POINT('',(-100.,-367.975001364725,101.111026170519));
#477=CARTESIAN_POINT('',(-100.,-366.235541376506,101.473518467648));
#478=CARTESIAN_POINT('',(-100.,-365.368413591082,101.667246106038));
#479=CARTESIAN_POINT('',(-100.,-363.640413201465,102.079230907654));
#480=CARTESIAN_POINT('',(-100.,-362.779537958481,102.297476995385));
#481=CARTESIAN_POINT('',(-100.,-361.064260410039,102.758114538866));
#482=CARTESIAN_POINT('',(-100.,-360.209858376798,103.000507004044));
#483=CARTESIAN_POINT('',(-100.,-357.694861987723,103.751876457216));
#484=CARTESIAN_POINT('',(-100.,-356.044121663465,104.294247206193));
#485=CARTESIAN_POINT('',(-100.,-352.772951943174,105.464438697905));
#486=CARTESIAN_POINT('',(-100.,-351.15252998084,106.09228009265));
#487=CARTESIAN_POINT('',(-100.,-347.944672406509,107.427397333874));
#488=CARTESIAN_POINT('',(-100.,-346.357238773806,108.134677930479));
#489=CARTESIAN_POINT('',(-100.,-343.548996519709,109.464747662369));
#490=CARTESIAN_POINT('',(-100.,-342.321635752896,110.07378288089));
#491=CARTESIAN_POINT('',(-100.,-339.888579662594,111.333764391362));
#492=CARTESIAN_POINT('',(-100.,-338.682885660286,111.984713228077));
#493=CARTESIAN_POINT('',(-100.,-335.096958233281,113.996077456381));
#494=CARTESIAN_POINT('',(-100.,-332.749052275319,115.414448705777));
#495=CARTESIAN_POINT('',(-100.,-328.135127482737,118.37926988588));
#496=CARTESIAN_POINT('',(-100.,-325.869141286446,119.925770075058));
#497=CARTESIAN_POINT('',(-100.,-321.375425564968,123.148180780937));
#498=CARTESIAN_POINT('',(-100.,-319.148915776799,124.825785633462));
#499=CARTESIAN_POINT('',(-100.,-315.859599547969,127.404797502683));
#500=CARTESIAN_POINT('',(-100.,-314.771816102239,128.274692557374));
#501=CARTESIAN_POINT('',(-100.,-312.611315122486,130.033023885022));
#502=CARTESIAN_POINT('',(-100.,-311.538597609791,130.921460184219));
#503=CARTESIAN_POINT('',(-100.,-309.407395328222,132.713930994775));
#504=CARTESIAN_POINT('',(-100.,-308.348902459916,133.617955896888));
#505=CARTESIAN_POINT('',(-100.,-306.24397217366,135.439903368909));
#506=CARTESIAN_POINT('',(-100.,-305.197534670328,136.357825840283));
#507=CARTESIAN_POINT('',(-100.,-302.935748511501,138.364695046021));
#508=CARTESIAN_POINT('',(-100.,-301.722366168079,139.455855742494));
#509=CARTESIAN_POINT('',(-100.,-299.307540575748,141.651321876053));
#510=CARTESIAN_POINT('',(-100.,-298.106097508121,142.75562751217));
#511=CARTESIAN_POINT('',(-100.,-295.712621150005,144.97451515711));
#512=CARTESIAN_POINT('',(-100.,-294.52058841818,146.089097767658));
#513=CARTESIAN_POINT('',(-100.,-292.143545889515,148.325732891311));
#514=CARTESIAN_POINT('',(-100.,-290.958536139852,149.447785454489));
#515=CARTESIAN_POINT('',(-100.,-287.408900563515,152.822609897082));
#516=CARTESIAN_POINT('',(-100.,-285.051184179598,155.082630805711));
#517=CARTESIAN_POINT('',(-100.,-280.33518532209,159.60194741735));
#518=CARTESIAN_POINT('',(-100.,-277.976902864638,161.861243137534));
#519=CARTESIAN_POINT('',(-100.,-273.233545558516,166.367096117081));
#520=CARTESIAN_POINT('',(-100.,-270.848408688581,168.613588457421));
#521=CARTESIAN_POINT('',(-100.,-266.040764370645,173.066506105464));
#522=CARTESIAN_POINT('',(-100.,-263.618256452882,175.272930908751));
#523=CARTESIAN_POINT('',(-100.,-258.770676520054,179.578217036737));
#524=CARTESIAN_POINT('',(-100.,-256.346756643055,181.678368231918));
#525=CARTESIAN_POINT('',(-100.,-251.431348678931,185.798287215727));
#526=CARTESIAN_POINT('',(-100.,-248.93986259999,187.818057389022));
#527=CARTESIAN_POINT('',(-100.,-243.881895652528,191.748462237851));
#528=CARTESIAN_POINT('',(-100.,-241.315625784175,193.659366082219));
#529=CARTESIAN_POINT('',(-100.,-237.397251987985,196.428451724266));
#530=CARTESIAN_POINT('',(-100.,-236.079479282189,197.335365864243));
#531=CARTESIAN_POINT('',(-100.,-233.41995379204,199.113268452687));
#532=CARTESIAN_POINT('',(-100.,-232.078202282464,199.984258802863));
#533=CARTESIAN_POINT('',(-100.,-229.37526784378,201.683430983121));
#534=CARTESIAN_POINT('',(-100.,-228.014183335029,202.511769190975));
#535=CARTESIAN_POINT('',(-100.,-225.267010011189,204.125748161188));
#536=CARTESIAN_POINT('',(-100.,-223.880922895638,204.911391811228));
#537=CARTESIAN_POINT('',(-100.,-221.084062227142,206.436228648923));
#538=CARTESIAN_POINT('',(-100.,-219.673297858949,207.175438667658));
#539=CARTESIAN_POINT('',(-100.,-216.826963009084,208.604214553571));
#540=CARTESIAN_POINT('',(-99.9999999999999,-215.391395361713,209.293786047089));
#541=CARTESIAN_POINT('',(-99.9999999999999,-213.313799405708,210.245479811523));
#542=CARTESIAN_POINT('',(-100.,-212.681532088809,210.529049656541));
#543=CARTESIAN_POINT('',(-100.,-211.412526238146,211.085914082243));
#544=CARTESIAN_POINT('',(-100.,-210.775787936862,211.359209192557));
#545=CARTESIAN_POINT('',(-100.,-208.858147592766,212.163667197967));
#546=CARTESIAN_POINT('',(-100.,-207.570580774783,212.679053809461));
#547=CARTESIAN_POINT('',(-100.,-204.978303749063,213.666055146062));
#548=CARTESIAN_POINT('',(-100.,-203.673588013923,214.137655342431));
#549=CARTESIAN_POINT('',(-100.,-201.048369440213,215.035376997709));
#550=CARTESIAN_POINT('',(-100.,-199.727864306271,215.46149175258));
#551=CARTESIAN_POINT('',(-100.,-197.072583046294,216.266850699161));
#552=CARTESIAN_POINT('',(-100.,-195.737806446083,216.646093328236));
#553=CARTESIAN_POINT('',(-100.,-193.052054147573,217.357606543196));
#554=CARTESIAN_POINT('',(-100.,-191.701045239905,217.689751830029));
#555=CARTESIAN_POINT('',(-100.,-188.98801371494,218.305183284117));
#556=CARTESIAN_POINT('',(-100.,-187.62599166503,218.588471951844));
#557=CARTESIAN_POINT('',(-100.,-184.892780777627,219.105849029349));
#558=CARTESIAN_POINT('',(-100.,-183.521592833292,219.339942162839));
#559=CARTESIAN_POINT('',(-100.,-180.771897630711,219.758899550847));
#560=CARTESIAN_POINT('',(-100.,-179.393391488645,219.943771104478));
#561=CARTESIAN_POINT('',(-100.,-177.321598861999,220.184285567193));
#562=CARTESIAN_POINT('',(-100.,-176.630401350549,220.258319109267));
#563=CARTESIAN_POINT('',(-100.,-175.246791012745,220.394201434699));
#564=CARTESIAN_POINT('',(-100.,-174.554378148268,220.456049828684));
#565=CARTESIAN_POINT('',(-100.,-172.407372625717,220.628908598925));
#566=CARTESIAN_POINT('',(-100.,-170.951047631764,220.719292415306));
#567=CARTESIAN_POINT('',(-100.,-168.764900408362,220.815566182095));
#568=CARTESIAN_POINT('',(-100.,-168.035867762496,220.841107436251));
#569=CARTESIAN_POINT('',(-100.,-166.577455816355,220.879210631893));
#570=CARTESIAN_POINT('',(-100.,-165.848076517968,220.891772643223));
#571=CARTESIAN_POINT('',(-100.,-164.388807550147,220.904331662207));
#572=CARTESIAN_POINT('',(-100.,-163.658917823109,220.904321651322));
#573=CARTESIAN_POINT('',(-100.,-162.199243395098,220.892257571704));
#574=CARTESIAN_POINT('',(-100.,-161.469458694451,220.880203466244));
#575=CARTESIAN_POINT('',(-100.,-159.280556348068,220.826707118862));
#576=CARTESIAN_POINT('',(-100.,-157.821833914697,220.767931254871));
#577=CARTESIAN_POINT('',(-100.,-154.906372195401,220.607833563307));
#578=CARTESIAN_POINT('',(-100.,-153.449633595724,220.506499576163));
#579=CARTESIAN_POINT('',(-100.,-150.539435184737,220.264648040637));
#580=CARTESIAN_POINT('',(-100.,-149.085975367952,220.124130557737));
#581=CARTESIAN_POINT('',(-100.,-146.175605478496,219.806165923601));
#582=CARTESIAN_POINT('',(-100.,-144.718715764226,219.628533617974));
#583=CARTESIAN_POINT('',(-100.,-141.809454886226,219.239601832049));
#584=CARTESIAN_POINT('',(-100.,-140.357083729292,219.028302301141));
#585=CARTESIAN_POINT('',(-100.,-137.457829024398,218.574687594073));
#586=CARTESIAN_POINT('',(-100.,-136.01094344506,218.332385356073));
#587=CARTESIAN_POINT('',(-100.,-133.122305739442,217.819010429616));
#588=CARTESIAN_POINT('',(-100.,-131.680553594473,217.547937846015));
#589=CARTESIAN_POINT('',(-100.,-128.802559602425,216.979162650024));
#590=CARTESIAN_POINT('',(-100.,-127.366316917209,216.68146427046));
#591=CARTESIAN_POINT('',(-100.,-124.499181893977,216.061292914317));
#592=CARTESIAN_POINT('',(-100.,-123.068289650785,215.738819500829));
#593=CARTESIAN_POINT('',(-100.,-119.265279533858,214.849468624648));
#594=CARTESIAN_POINT('',(-100.,-116.897898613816,214.262261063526));
#595=CARTESIAN_POINT('',(-100.,-112.177903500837,213.031167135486));
#596=CARTESIAN_POINT('',(-100.,-109.82528990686,212.387278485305));
#597=CARTESIAN_POINT('',(-100.,-105.133606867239,211.048545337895));
#598=CARTESIAN_POINT('',(-100.,-102.794543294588,210.353680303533));
#599=CARTESIAN_POINT('',(-100.,-98.1304961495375,208.918409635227));
#600=CARTESIAN_POINT('',(-100.,-95.8055124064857,208.178004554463));
#601=CARTESIAN_POINT('',(-100.,-91.1663376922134,206.655239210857));
#602=CARTESIAN_POINT('',(-100.,-88.8521625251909,205.872830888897));
#603=CARTESIAN_POINT('',(-100.,-84.236752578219,204.27077465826));
#604=CARTESIAN_POINT('',(-100.,-81.9355178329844,203.451126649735));
#605=CARTESIAN_POINT('',(-100.,-77.3428441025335,201.777106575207));
#606=CARTESIAN_POINT('',(-100.,-75.0514187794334,200.922697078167));
#607=CARTESIAN_POINT('',(-100.,-70.4803179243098,199.183048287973));
#608=CARTESIAN_POINT('',(-100.,-68.2006423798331,198.297809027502));
#609=CARTESIAN_POINT('',(-100.,-63.6511210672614,196.498678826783));
#610=CARTESIAN_POINT('',(-100.,-61.3812817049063,195.584771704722));
#611=CARTESIAN_POINT('',(-100.,-56.8521550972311,193.731196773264));
#612=CARTESIAN_POINT('',(-100.,-54.5928678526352,192.7915289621));
#613=CARTESIAN_POINT('',(-100.,-50.0848332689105,190.888828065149));
#614=CARTESIAN_POINT('',(-100.,-47.8360834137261,189.925800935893));
#615=CARTESIAN_POINT('',(-100.,-43.3479886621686,187.978091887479));
#616=CARTESIAN_POINT('',(-100.,-41.1086437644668,186.99340997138));
#617=CARTESIAN_POINT('',(-100.,-36.6319123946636,185.001074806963));
#618=CARTESIAN_POINT('',(-100.,-34.3945533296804,183.993360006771));
#619=CARTESIAN_POINT('',(-100.,-29.9282188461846,181.959509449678));
#620=CARTESIAN_POINT('',(-100.,-27.6992434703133,180.933373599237));
#621=CARTESIAN_POINT('',(-100.,-21.0287812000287,177.831740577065));
#622=CARTESIAN_POINT('',(-100.,-16.5990544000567,175.730917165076));
#623=CARTESIAN_POINT('',(-100.,-7.77018143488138,171.473546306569));
#624=CARTESIAN_POINT('',(-100.,-3.37101683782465,169.317036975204));
#625=CARTESIAN_POINT('',(-100.,5.4016473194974,164.956641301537));
#626=CARTESIAN_POINT('',(-100.,9.77515603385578,162.75277335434));
#627=CARTESIAN_POINT('',(-100.,18.5008901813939,158.305037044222));
#628=CARTESIAN_POINT('',(-100.,22.8531188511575,156.061175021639));
#629=CARTESIAN_POINT('',(-100.,31.5403230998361,151.540096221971));
#630=CARTESIAN_POINT('',(-100.,35.8752982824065,149.262878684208));
#631=CARTESIAN_POINT('',(-100.,44.1065519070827,144.906304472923));
#632=CARTESIAN_POINT('',(-100.,48.0041555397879,142.829448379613));
#633=CARTESIAN_POINT('',(-100.,55.7907242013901,138.658114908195));
#634=CARTESIAN_POINT('',(-100.,59.6796877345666,136.563634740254));
#635=CARTESIAN_POINT('',(-100.,67.4512640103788,132.36147530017));
#636=CARTESIAN_POINT('',(-100.,71.333875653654,130.253793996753));
#637=CARTESIAN_POINT('',(-100.,79.0950538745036,126.029684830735));
#638=CARTESIAN_POINT('',(-100.,82.9736197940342,123.913255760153));
#639=CARTESIAN_POINT('',(-100.,90.7290912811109,119.676250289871));
#640=CARTESIAN_POINT('',(-100.,94.6059965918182,117.55567342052));
#641=CARTESIAN_POINT('',(-100.,102.360681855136,113.315246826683));
#642=CARTESIAN_POINT('',(-100.,106.238461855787,111.195397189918));
#643=CARTESIAN_POINT('',(-100.,113.992513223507,106.964554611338));
#644=CARTESIAN_POINT('',(-100.,117.868780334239,104.853553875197));
#645=CARTESIAN_POINT('',(-100.,125.627726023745,100.643680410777));
#646=CARTESIAN_POINT('',(-100.,129.510404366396,98.5448072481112));
#647=CARTESIAN_POINT('',(-100.,135.341834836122,95.4108259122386));
#648=CARTESIAN_POINT('',(-100.,137.286768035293,94.3686132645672));
#649=CARTESIAN_POINT('',(-100.,141.179694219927,92.2899199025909));
#650=CARTESIAN_POINT('',(-100.,143.127687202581,91.2534391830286));
#651=CARTESIAN_POINT('',(-100.,147.026952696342,89.1874653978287));
#652=CARTESIAN_POINT('',(-100.,148.978224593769,88.1579711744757));
#653=CARTESIAN_POINT('',(-100.,152.884981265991,86.1070053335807));
#654=CARTESIAN_POINT('',(-100.,154.840466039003,85.0855337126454));
#655=CARTESIAN_POINT('',(-100.,158.755969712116,83.0521571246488));
#656=CARTESIAN_POINT('',(-100.,160.715987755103,82.0402505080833));
#657=CARTESIAN_POINT('',(-100.,164.641641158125,80.0273754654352));
#658=CARTESIAN_POINT('',(-100.,166.607276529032,79.0264070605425));
#659=CARTESIAN_POINT('',(-100.,170.544820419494,77.037285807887));
#660=CARTESIAN_POINT('',(-100.,172.516728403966,76.0491319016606));
#661=CARTESIAN_POINT('',(-100.,176.467895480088,74.0876456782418));
#662=CARTESIAN_POINT('',(-100.,178.4471545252,73.1143132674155));
#663=CARTESIAN_POINT('',(-100.,182.022125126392,71.3755752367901));
#664=CARTESIAN_POINT('',(-100.,183.616338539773,70.6070902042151));
#665=CARTESIAN_POINT('',(-100.,186.810880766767,69.0827156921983));
#666=CARTESIAN_POINT('',(-100.,188.411209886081,68.3268268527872));
#667=CARTESIAN_POINT('',(-100.,191.61874550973,66.8293576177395));
#668=CARTESIAN_POINT('',(-100.,193.225952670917,66.0877786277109));
#669=CARTESIAN_POINT('',(-100.,196.448144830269,64.6209376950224));
#670=CARTESIAN_POINT('',(-100.,198.063131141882,63.895678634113));
#671=CARTESIAN_POINT('',(-100.,201.301956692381,62.4638637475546));
#672=CARTESIAN_POINT('',(-100.,202.925798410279,61.7573135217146));
#673=CARTESIAN_POINT('',(-100.,206.180313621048,60.3671977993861));
#674=CARTESIAN_POINT('',(-100.,207.810972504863,59.6835981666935));
#675=CARTESIAN_POINT('',(-100.,211.082809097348,58.3418856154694));
#676=CARTESIAN_POINT('',(-100.,212.723987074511,57.6837733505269));
#677=CARTESIAN_POINT('',(-100.,216.017818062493,56.3980050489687));
#678=CARTESIAN_POINT('',(-100.,217.670468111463,55.7703414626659));
#679=CARTESIAN_POINT('',(-100.,220.159214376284,54.8563480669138));
#680=CARTESIAN_POINT('',(-100.,220.990287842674,54.5563142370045));
#681=CARTESIAN_POINT('',(-100.,222.656006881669,53.9663431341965));
#682=CARTESIAN_POINT('',(-100.,223.490652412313,53.6764057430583));
#683=CARTESIAN_POINT('',(-100.,225.163630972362,53.1077544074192));
#684=CARTESIAN_POINT('',(-100.,226.001963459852,52.829038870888));
#685=CARTESIAN_POINT('',(-100.,227.682661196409,52.2840703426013));
#686=CARTESIAN_POINT('',(-100.,228.525026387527,52.0178171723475));
#687=CARTESIAN_POINT('',(-100.,230.430703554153,51.432738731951));
#688=CARTESIAN_POINT('',(-100.,231.495259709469,51.1179491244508));
#689=CARTESIAN_POINT('',(-100.,233.631651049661,50.5139537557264));
#690=CARTESIAN_POINT('',(-100.,234.703486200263,50.2247478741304));
#691=CARTESIAN_POINT('',(-100.,236.317042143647,49.813529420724));
#692=CARTESIAN_POINT('',(-100.,236.855893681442,49.6802143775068));
#693=CARTESIAN_POINT('',(-100.,237.935572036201,49.4218104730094));
#694=CARTESIAN_POINT('',(-100.,238.47639885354,49.2967216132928));
#695=CARTESIAN_POINT('',(-100.,239.560240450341,49.0554821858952));
#696=CARTESIAN_POINT('',(-100.,240.103255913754,48.9393346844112));
#697=CARTESIAN_POINT('',(-100.,241.191313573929,48.7169428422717));
#698=CARTESIAN_POINT('',(-100.,241.736355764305,48.6106984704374));
#699=CARTESIAN_POINT('',(-100.,242.828394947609,48.4088730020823));
#700=CARTESIAN_POINT('',(-100.,243.375391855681,48.3132914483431));
#701=CARTESIAN_POINT('',(-100.,244.471233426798,48.1334313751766));
#702=CARTESIAN_POINT('',(-100.,245.02007810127,48.0491529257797));
#703=CARTESIAN_POINT('',(-100.,246.669123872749,47.8143506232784));
#704=CARTESIAN_POINT('',(-100.,247.771982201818,47.6818325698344));
#705=CARTESIAN_POINT('',(-100.,249.799391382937,47.488542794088));
#706=CARTESIAN_POINT('',(-100.,250.7231578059,47.4195138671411));
#707=CARTESIAN_POINT('',(-100.,252.572917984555,47.3231181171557));
#708=CARTESIAN_POINT('',(-100.,253.498911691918,47.2957503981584));
#709=CARTESIAN_POINT('',(-100.,255.351237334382,47.2867845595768));
#710=CARTESIAN_POINT('',(-100.,256.277569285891,47.3051890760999));
#711=CARTESIAN_POINT('',(-100.,258.125623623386,47.3918042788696));
#712=CARTESIAN_POINT('',(-100.,259.0473517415,47.4598884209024));
#713=CARTESIAN_POINT('',(-100.,260.885347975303,47.6496028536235));
#714=CARTESIAN_POINT('',(-100.,261.801616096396,47.7712330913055));
#715=CARTESIAN_POINT('',(-100.,263.624852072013,48.0713859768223));
#716=CARTESIAN_POINT('',(-100.,264.531820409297,48.2499056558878));
#717=CARTESIAN_POINT('',(-100.,266.116172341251,48.6162487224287));
#718=CARTESIAN_POINT('',(-100.,266.796463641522,48.7915790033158));
#719=CARTESIAN_POINT('',(-100.,268.147274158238,49.1770229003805));
#720=CARTESIAN_POINT('',(-100.,268.817791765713,49.3871421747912));
#721=CARTESIAN_POINT('',(-100.,270.14688962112,49.8421388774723));
#722=CARTESIAN_POINT('',(-100.,270.805470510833,50.0870144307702));
#723=CARTESIAN_POINT('',(-100.,272.108756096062,50.6109176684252));
#724=CARTESIAN_POINT('',(-100.,272.753463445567,50.8899387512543));
#725=CARTESIAN_POINT('',(-100.,274.027932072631,51.4812240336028));
#726=CARTESIAN_POINT('',(-100.,274.657683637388,51.7935091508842));
#727=CARTESIAN_POINT('',(-100.,275.900629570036,52.4495500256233));
#728=CARTESIAN_POINT('',(-100.,276.513822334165,52.7933088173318));
#729=CARTESIAN_POINT('',(-100.,277.722849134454,53.510227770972));
#730=CARTESIAN_POINT('',(-100.,278.318680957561,53.883391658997));
#731=CARTESIAN_POINT('',(-100.,279.492441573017,54.6565955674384));
#732=CARTESIAN_POINT('',(-100.,280.070373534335,55.056630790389));
#733=CARTESIAN_POINT('',(-100.,281.349118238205,55.9828614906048));
#734=CARTESIAN_POINT('',(-100.,282.045034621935,56.5158176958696));
#735=CARTESIAN_POINT('',(-100.,283.410402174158,57.6143236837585));
#736=CARTESIAN_POINT('',(-100.,284.079855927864,58.1798702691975));
#737=CARTESIAN_POINT('',(-100.,285.394398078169,59.3385361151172));
#738=CARTESIAN_POINT('',(-100.,286.039485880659,59.9316560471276));
#739=CARTESIAN_POINT('',(-100.,287.309483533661,61.1421580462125));
#740=CARTESIAN_POINT('',(-100.,287.934338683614,61.7595972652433));
#741=CARTESIAN_POINT('',(-100.,289.165188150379,63.0128086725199));
#742=CARTESIAN_POINT('',(-100.,289.77118426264,63.6485791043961));
#743=CARTESIAN_POINT('',(-100.,290.967645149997,64.9343667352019));
#744=CARTESIAN_POINT('',(-100.,291.558111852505,65.5843821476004));
#745=CARTESIAN_POINT('',(-100.,292.699615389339,66.8642692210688));
#746=CARTESIAN_POINT('',(-100.,293.251201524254,67.493652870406));
#747=CARTESIAN_POINT('',(-100.,294.346565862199,68.7591876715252));
#748=CARTESIAN_POINT('',(-100.,294.89034384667,69.3953390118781));
#749=CARTESIAN_POINT('',(-100.,295.973201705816,70.6717810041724));
#750=CARTESIAN_POINT('',(-100.,296.512280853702,71.3120722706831));
#751=CARTESIAN_POINT('',(-100.,297.58866231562,72.5941517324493));
#752=CARTESIAN_POINT('',(-100.,298.125964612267,73.2359399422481));
#753=CARTESIAN_POINT('',(-100.,299.740383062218,75.1607408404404));
#754=CARTESIAN_POINT('',(-100.,300.819259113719,76.4422869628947));
#755=CARTESIAN_POINT('',(-100.,303.000432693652,78.977592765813));
#756=CARTESIAN_POINT('',(-100.,304.102631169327,80.2314363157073));
#757=CARTESIAN_POINT('',(-100.,305.791148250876,82.0795570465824));
#758=CARTESIAN_POINT('',(-100.,306.359715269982,82.6900126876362));
#759=CARTESIAN_POINT('',(-100.,307.510908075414,83.8974953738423));
#760=CARTESIAN_POINT('',(-100.,308.093533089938,84.4945231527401));
#761=CARTESIAN_POINT('',(-100.,309.274584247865,85.672109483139));
#762=CARTESIAN_POINT('',(-100.,309.873001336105,86.2526770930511));
#763=CARTESIAN_POINT('',(-100.,311.087651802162,87.3948143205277));
#764=CARTESIAN_POINT('',(-100.,311.70388367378,87.9563855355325));
#765=CARTESIAN_POINT('',(-100.,312.922657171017,89.0286973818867));
#766=CARTESIAN_POINT('',(-100.,313.524211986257,89.5405576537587));
#767=CARTESIAN_POINT('',(-100.,314.745601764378,90.542335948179));
#768=CARTESIAN_POINT('',(-100.,315.365441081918,91.0322486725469));
#769=CARTESIAN_POINT('',(-100.,316.623722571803,91.9875835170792));
#770=CARTESIAN_POINT('',(-100.,317.262164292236,92.4530062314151));
#771=CARTESIAN_POINT('',(-100.,318.557748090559,93.3571087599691));
#772=CARTESIAN_POINT('',(-100.,319.214890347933,93.7957883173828));
#773=CARTESIAN_POINT('',(-100.,320.546173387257,94.6434789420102));
#774=CARTESIAN_POINT('',(-100.,321.220276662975,95.0525488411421));
#775=CARTESIAN_POINT('',(-100.,322.586119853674,95.8403039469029));
#776=CARTESIAN_POINT('',(-100.,323.277861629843,96.2189859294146));
#777=CARTESIAN_POINT('',(-100.,324.677812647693,96.944525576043));
#778=CARTESIAN_POINT('',(-100.,325.38602125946,97.2913844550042));
#779=CARTESIAN_POINT('',(-100.,326.81749704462,97.9523006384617));
#780=CARTESIAN_POINT('',(-100.,327.540762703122,98.2663612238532));
#781=CARTESIAN_POINT('',(-100.,328.999904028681,98.8608164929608));
#782=CARTESIAN_POINT('',(-100.,329.735762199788,99.1412541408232));
#783=CARTESIAN_POINT('',(-100.,331.219383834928,99.6688789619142));
#784=CARTESIAN_POINT('',(-100.,331.967148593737,99.9160624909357));
#785=CARTESIAN_POINT('',(-100.,333.47279257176,100.377470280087));
#786=CARTESIAN_POINT('',(-100.,334.230672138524,100.591693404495));
#787=CARTESIAN_POINT('',(-100.,335.754784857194,100.987836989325));
#788=CARTESIAN_POINT('',(-100.,336.521017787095,101.169758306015));
#789=CARTESIAN_POINT('',(-100.,338.065980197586,101.503506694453));
#790=CARTESIAN_POINT('',(-100.,338.844760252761,101.655099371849));
#791=CARTESIAN_POINT('',(-100.,340.407679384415,101.927705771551));
#792=CARTESIAN_POINT('',(-100.,341.19181900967,102.048716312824));
#793=CARTESIAN_POINT('',(-100.,343.549932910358,102.367858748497));
#794=CARTESIAN_POINT('',(-100.,345.130015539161,102.522189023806));
#795=CARTESIAN_POINT('',(-100.,347.910348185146,102.701029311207));
#796=CARTESIAN_POINT('',(-100.,349.109302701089,102.748013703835));
#797=CARTESIAN_POINT('',(-100.,351.508437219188,102.787253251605));
#798=CARTESIAN_POINT('',(-100.,352.708617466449,102.779493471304));
#799=CARTESIAN_POINT('',(-100.,355.108405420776,102.714220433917));
#800=CARTESIAN_POINT('',(-100.,356.308012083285,102.656671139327));
#801=CARTESIAN_POINT('',(-100.,358.704977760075,102.496438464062));
#802=CARTESIAN_POINT('',(-100.,359.902334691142,102.393724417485));
#803=CARTESIAN_POINT('',(-100.,362.26812354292,102.150013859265));
#804=CARTESIAN_POINT('',(-100.,363.436642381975,102.009851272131));
#805=CARTESIAN_POINT('',(-100.,365.768225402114,101.694113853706));
#806=CARTESIAN_POINT('',(-100.,366.931292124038,101.518557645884));
#807=CARTESIAN_POINT('',(-100.,369.250252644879,101.135566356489));
#808=CARTESIAN_POINT('',(-100.,370.406154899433,100.928182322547));
#809=CARTESIAN_POINT('',(-100.,372.134103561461,100.595547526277));
#810=CARTESIAN_POINT('',(-100.,372.708286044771,100.48125477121));
#811=CARTESIAN_POINT('',(-100.,373.855217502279,100.245742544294));
#812=CARTESIAN_POINT('',(-100.,374.427966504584,100.124523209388));
#813=CARTESIAN_POINT('',(-100.,375.,100.));
#814=B_SPLINE_CURVE_WITH_KNOTS('',3,(#470,#471,#472,#473,#474,#475,#476,#477,#478,#479,#480,
#481,#482,#483,#484,#485,#486,#487,#488,#489,#490,#491,#492,#493,#494,#495,#496,#497,#498,#499,
#500,#501,#502,#503,#504,#505,#506,#507,#508,#509,#510,#511,#512,#513,#514,#515,#516,#517,#518,
#519,#520,#521,#522,#523,#524,#525,#526,#527,#528,#529,#530,#531,#532,#533,#534,#535,#536,#537,
#538,#539,#540,#541,#542,#543,#544,#545,#546,#547,#548,#549,#550,#551,#552,#553,#554,#555,#556,
#557,#558,#559,#560,#561,#562,#563,#564,#565,#566,#567,#568,#569,#570,#571,#572,#573,#574,#575,
#576,#577,#578,#579,#580,#581,#582,#583,#584,#585,#586,#587,#588,#589,#590,#591,#592,#593,#594,
#595,#596,#597,#598,#599,#600,#601,#602,#603,#604,#605,#606,#607,#608,#609,#610,#611,#612,#613,
#614,#615,#616,#617,#618,#619,#620,#621,#622,#623,#624,#625,#626,#627,#628,#629,#630,#631,#632,
#633,#634,#635,#636,#637,#638,#639,#640,#641,#642,#643,#644,#645,#646,#647,#648,#649,#650,#651,
#652,#653,#654,#655,#656,#657,#658,#659,#660,#661,#662,#663,#664,#665,#666,#667,#668,#669,#670,
#671,#672,#673,#674,#675,#676,#677,#678,#679,#680,#681,#682,#683,#684,#685,#686,#687,#688,#689,
#690,#691,#692,#693,#694,#695,#696,#697,#698,#699,#700,#701,#702,#703,#704,#705,#706,#707,#708,
#709,#710,#711,#712,#713,#714,#715,#716,#717,#718,#719,#720,#721,#722,#723,#724,#725,#726,#727,
#728,#729,#730,#731,#732,#733,#734,#735,#736,#737,#738,#739,#740,#741,#742,#743,#744,#745,#746,
#747,#748,#749,#750,#751,#752,#753,#754,#755,#756,#757,#758,#759,#760,#761,#762,#763,#764,#765,
#766,#767,#768,#769,#770,#771,#772,#773,#774,#775,#776,#777,#778,#779,#780,#781,#782,#783,#784,
#785,#786,#787,#788,#789,#790,#791,#792,#793,#794,#795,#796,#797,#798,#799,#800,#801,#802,#803,
#804,#805,#806,#807,#808,#809,#810,#811,#812,#813),.UNSPECIFIED.,.F.,.F.,(4,2,2,2,2,2,2,2,2,2,2,
2,2,2,2,2,2,2,2,2,2,2,2,2,2,2,2,2,2,2,2,2,2,2,2,2,2,2,2,2,2,2,2,2,2,2,2,2,2,2,2,2,2,2,2,2,2,2,2,
2,2,2,2,2,2,2,2,2,2,2,2,2,2,2,2,2,2,2,2,2,2,2,2,2,2,2,2,2,2,2,2,2,2,2,2,2,2,2,2,2,2,2,2,2,2,2,2,
2,2,2,2,2,2,2,2,2,2,2,2,2,2,2,2,2,2,2,2,2,2,2,2,2,2,2,2,2,2,2,2,2,2,2,2,2,2,2,2,2,2,2,2,2,2,2,2,
2,2,2,2,2,2,2,2,2,2,2,2,2,2,2,2,4),(0.,2.66844053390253,5.33685713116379,8.00200962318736,
10.6671646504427,13.3311205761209,15.9951879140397,21.2051538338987,26.4163808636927,
31.6279196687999,35.7375674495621,39.8474649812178,48.071153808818,56.2980837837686,
64.6586796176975,68.8370337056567,73.015393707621,77.1912641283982,81.3671049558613,
86.2625261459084,91.1580215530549,96.0538054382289,100.949622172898,110.747481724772,
120.545088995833,130.374415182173,140.203865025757,149.824091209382,159.444031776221,
169.039051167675,173.837648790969,178.635992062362,183.415265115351,188.194214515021,
192.971421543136,197.748086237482,199.826848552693,201.905503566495,206.065323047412,
210.226517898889,214.388325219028,218.550271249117,222.723090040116,226.895695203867,
231.067899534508,235.239484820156,237.324842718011,239.410267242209,243.786492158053,
245.974846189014,248.163188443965,250.352752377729,252.542322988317,256.921294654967,
261.301518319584,265.681734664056,270.084347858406,274.486967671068,278.887756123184,
283.288528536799,287.688602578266,292.088754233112,299.40525661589,306.722053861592,
314.041815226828,321.361487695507,328.689721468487,336.017974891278,343.35433978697,
350.690696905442,358.031272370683,365.371848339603,372.710571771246,380.049294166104,
387.410681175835,394.772105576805,409.479501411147,424.177084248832,438.869057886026,
453.558722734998,468.248723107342,481.497889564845,494.74919432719,508.002590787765,
521.257883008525,534.514774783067,547.772920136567,561.014358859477,574.255320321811,
580.875037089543,587.494747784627,594.11333335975,600.731916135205,607.349335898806,
613.966768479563,620.583650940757,627.20049158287,632.509754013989,637.81928539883,
643.129335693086,648.440316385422,653.752869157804,659.057134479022,664.361535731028,
669.664614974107,672.315284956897,674.965923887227,677.616185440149,680.266409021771,
683.596509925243,686.926595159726,688.591836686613,690.25707853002,691.922888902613,
693.588694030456,695.254427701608,696.920171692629,700.251215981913,703.029429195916,
705.807582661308,708.585896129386,711.357157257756,714.128415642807,716.899529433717,
719.006233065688,721.113279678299,723.220212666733,725.326738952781,727.434597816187,
729.54266010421,731.650989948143,733.758944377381,736.387419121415,739.015636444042,
741.643917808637,744.278795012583,746.913420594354,749.547717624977,752.058274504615,
754.568901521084,757.079910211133,759.590943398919,764.616534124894,769.623911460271,
772.126388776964,774.628729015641,777.129664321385,779.630388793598,781.999479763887,
784.369139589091,786.73874189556,789.108366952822,791.473146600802,793.838176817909,
796.203116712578,798.567819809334,800.929468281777,803.291375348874,805.653363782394,
808.015289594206,810.394818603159,812.774595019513,817.532883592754,821.131332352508,
824.730762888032,828.33280086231,831.937288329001,835.467377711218,838.995614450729,
842.518250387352,844.274556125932,846.030827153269),.UNSPECIFIED.);
#815=CARTESIAN_POINT('',(-100.,-375.,100.));
#816=VERTEX_POINT('',#815);
#817=CARTESIAN_POINT('',(-100.,375.,100.));
#818=VERTEX_POINT('',#817);
#819=EDGE_CURVE('E11',#816,#818,#814,.T.);
#820=CARTESIAN_POINT('',(-750.,-375.,100.));
#821=CARTESIAN_POINT('',(-644.685568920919,-375.,100.));
#822=CARTESIAN_POINT('',(-536.684515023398,-375.,100.));
#823=CARTESIAN_POINT('',(-355.235514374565,-375.,100.));
#824=CARTESIAN_POINT('',(-175.903454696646,-375.,100.));
#825=CARTESIAN_POINT('',(47.4554331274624,-375.,100.));
#826=CARTESIAN_POINT('',(285.091607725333,-375.,100.));
#827=CARTESIAN_POINT('',(500.445116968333,-375.,100.));
#828=CARTESIAN_POINT('',(669.085175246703,-375.,100.));
#829=CARTESIAN_POINT('',(750.,-375.,100.));
#830=B_SPLINE_CURVE_WITH_KNOTS('',3,(#820,#821,#822,#823,#824,#825,#826,#827,#828,#829),
.UNSPECIFIED.,.F.,.F.,(4,1,1,1,1,1,1,4),(0.,0.210628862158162,0.216002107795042,
0.362898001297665,0.569292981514,0.66271988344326,0.838170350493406,1.),.UNSPECIFIED.);
#831=EDGE_CURVE('E97',#816,#330,#830,.T.);
#832=CARTESIAN_POINT('',(750.,375.,100.));
#833=CARTESIAN_POINT('',(669.085175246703,375.,100.));
#834=CARTESIAN_POINT('',(500.445116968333,375.,100.));
#835=CARTESIAN_POINT('',(285.091607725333,375.,100.));
#836=CARTESIAN_POINT('',(47.4554331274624,375.,100.));
#837=CARTESIAN_POINT('',(-175.903454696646,375.,100.));
#838=CARTESIAN_POINT('',(-355.235514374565,375.,100.));
#839=CARTESIAN_POINT('',(-536.684515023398,375.,100.));
#840=CARTESIAN_POINT('',(-644.685568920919,375.,100.));
#841=CARTESIAN_POINT('',(-750.,375.,100.));
#842=B_SPLINE_CURVE_WITH_KNOTS('',3,(#832,#833,#834,#835,#836,#837,#838,#839,#840,#841),
.UNSPECIFIED.,.F.,.F.,(4,1,1,1,1,1,1,4),(0.,0.161829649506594,0.33728011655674,0.430707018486,
0.637101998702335,0.783997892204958,0.789371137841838,1.),.UNSPECIFIED.);
#843=EDGE_CURVE('E94',#328,#818,#842,.T.);
#844=ORIENTED_EDGE('',*,*,#819,.F.);
#845=ORIENTED_EDGE('',*,*,#831,.T.);
#846=ORIENTED_EDGE('',*,*,#331,.F.);
#847=ORIENTED_EDGE('',*,*,#843,.T.);
#848=EDGE_LOOP('',(#844,#845,#846,#847));
#849=FACE_BOUND('',#848,.T.);
#850=ADVANCED_FACE('F110',(#849),#469,.F.);
#851=CARTESIAN_POINT('',(-750.,375.,253.111113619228));
#852=DIRECTION('',(0.,-1.,0.));
#853=DIRECTION('',(0.,0.,-1.));
#854=AXIS2_PLACEMENT_3D('',#851,#852,#853);
#855=PLANE('',#854);
#856=DIRECTION('',(0.,0.,-1.));
#857=VECTOR('',#856,1.);
#858=CARTESIAN_POINT('',(-100.,375.,253.120113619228));
#859=LINE('',#858,#857);
#860=EDGE_CURVE('E154',#818,#376,#859,.T.);
#861=ORIENTED_EDGE('',*,*,#860,.F.);
#862=ORIENTED_EDGE('',*,*,#843,.F.);
#863=ORIENTED_EDGE('',*,*,#353,.T.);
#864=ORIENTED_EDGE('',*,*,#383,.T.);
#865=EDGE_LOOP('',(#861,#862,#863,#864));
#866=FACE_BOUND('',#865,.T.);
#867=ADVANCED_FACE('F121',(#866),#855,.F.);
#868=CARTESIAN_POINT('',(-750.,-375.,253.111113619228));
#869=DIRECTION('',(0.,1.,0.));
#870=DIRECTION('',(0.,0.,1.));
#871=AXIS2_PLACEMENT_3D('',#868,#869,#870);
#872=PLANE('',#871);
#873=DIRECTION('',(0.,0.,-1.));
#874=VECTOR('',#873,1.);
#875=CARTESIAN_POINT('',(-100.,-375.,253.120113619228));
#876=LINE('',#875,#874);
#877=EDGE_CURVE('E56',#816,#368,#876,.T.);
#878=ORIENTED_EDGE('',*,*,#877,.T.);
#879=ORIENTED_EDGE('',*,*,#369,.T.);
#880=ORIENTED_EDGE('',*,*,#339,.F.);
#881=ORIENTED_EDGE('',*,*,#831,.F.);
#882=EDGE_LOOP('',(#878,#879,#880,#881));
#883=FACE_BOUND('',#882,.T.);
#884=ADVANCED_FACE('F37',(#883),#872,.F.);
#885=CARTESIAN_POINT('',(-100.,375.,253.120113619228));
#886=DIRECTION('',(-1.,0.,0.));
#887=DIRECTION('',(0.,-1.,0.));
#888=AXIS2_PLACEMENT_3D('',#885,#886,#887);
#889=PLANE('',#888);
#890=ORIENTED_EDGE('',*,*,#819,.T.);
#891=ORIENTED_EDGE('',*,*,#860,.T.);
#892=ORIENTED_EDGE('',*,*,#377,.F.);
#893=ORIENTED_EDGE('',*,*,#877,.F.);
#894=EDGE_LOOP('',(#890,#891,#892,#893));
#895=FACE_BOUND('',#894,.T.);
#896=ADVANCED_FACE('F145',(#895),#889,.T.);
#897=CLOSED_SHELL('',(#357,#388,#850,#867,#884,#896));
#898=MANIFOLD_SOLID_BREP('B2',#897);
#899=ADVANCED_BREP_SHAPE_REPRESENTATION('',(#18,#898),#14);
#900=SHAPE_DEFINITION_REPRESENTATION(#9,#899);
ENDSEC;
END-ISO-10303-21;
